VERSION 5.7 ;
  NOWIREEXTENSIONATPIN ON ;
  DIVIDERCHAR "/" ;
  BUSBITCHARS "[]" ;
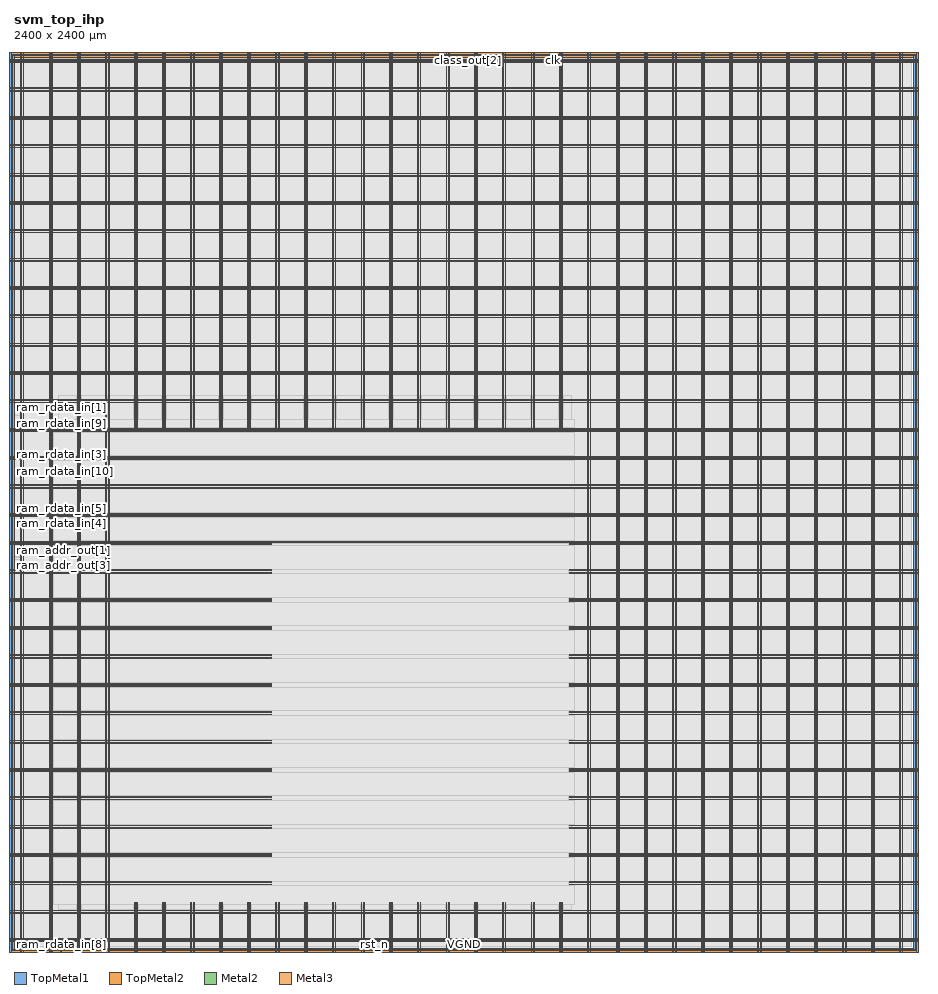
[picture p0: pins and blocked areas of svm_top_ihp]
MACRO svm_top_ihp
  CLASS BLOCK ;
  FOREIGN svm_top_ihp ;
  ORIGIN 0.000 0.000 ;
  SIZE 2400.000 BY 2400.000 ;
  PIN VGND
    DIRECTION INOUT ;
    USE GROUND ;
    PORT
      LAYER TopMetal1 ;
        RECT -10.740 -1.380 -5.740 2397.900 ;
    END
    PORT
      LAYER TopMetal1 ;
        RECT 2405.740 -1.380 2410.740 2397.900 ;
    END
    PORT
      LAYER TopMetal2 ;
        RECT -10.740 -1.380 2410.740 3.620 ;
    END
    PORT
      LAYER TopMetal2 ;
        RECT -10.740 2392.900 2410.740 2397.900 ;
    END
    PORT
      LAYER TopMetal1 ;
        RECT 24.460 -1.380 26.660 2397.900 ;
    END
    PORT
      LAYER TopMetal1 ;
        RECT 100.060 -1.380 102.260 2397.900 ;
    END
    PORT
      LAYER TopMetal1 ;
        RECT 175.660 -1.380 177.860 2397.900 ;
    END
    PORT
      LAYER TopMetal1 ;
        RECT 251.260 -1.380 253.460 2397.900 ;
    END
    PORT
      LAYER TopMetal1 ;
        RECT 326.860 -1.380 329.060 131.600 ;
    END
    PORT
      LAYER TopMetal1 ;
        RECT 326.860 1387.620 329.060 2397.900 ;
    END
    PORT
      LAYER TopMetal1 ;
        RECT 402.460 -1.380 404.660 131.600 ;
    END
    PORT
      LAYER TopMetal1 ;
        RECT 402.460 1387.620 404.660 2397.900 ;
    END
    PORT
      LAYER TopMetal1 ;
        RECT 478.060 -1.380 480.260 131.600 ;
    END
    PORT
      LAYER TopMetal1 ;
        RECT 478.060 1387.620 480.260 2397.900 ;
    END
    PORT
      LAYER TopMetal1 ;
        RECT 553.660 -1.380 555.860 131.600 ;
    END
    PORT
      LAYER TopMetal1 ;
        RECT 553.660 1387.620 555.860 2397.900 ;
    END
    PORT
      LAYER TopMetal1 ;
        RECT 629.260 -1.380 631.460 131.600 ;
    END
    PORT
      LAYER TopMetal1 ;
        RECT 629.260 1387.620 631.460 2397.900 ;
    END
    PORT
      LAYER TopMetal1 ;
        RECT 704.860 -1.380 707.060 131.600 ;
    END
    PORT
      LAYER TopMetal1 ;
        RECT 704.860 1387.620 707.060 2397.900 ;
    END
    PORT
      LAYER TopMetal1 ;
        RECT 780.460 -1.380 782.660 131.600 ;
    END
    PORT
      LAYER TopMetal1 ;
        RECT 780.460 1387.620 782.660 2397.900 ;
    END
    PORT
      LAYER TopMetal1 ;
        RECT 856.060 -1.380 858.260 131.600 ;
    END
    PORT
      LAYER TopMetal1 ;
        RECT 856.060 1387.620 858.260 2397.900 ;
    END
    PORT
      LAYER TopMetal1 ;
        RECT 931.660 -1.380 933.860 131.600 ;
    END
    PORT
      LAYER TopMetal1 ;
        RECT 931.660 1387.620 933.860 2397.900 ;
    END
    PORT
      LAYER TopMetal1 ;
        RECT 1007.260 -1.380 1009.460 131.600 ;
    END
    PORT
      LAYER TopMetal1 ;
        RECT 1007.260 1387.620 1009.460 2397.900 ;
    END
    PORT
      LAYER TopMetal1 ;
        RECT 1082.860 -1.380 1085.060 131.600 ;
    END
    PORT
      LAYER TopMetal1 ;
        RECT 1082.860 1387.620 1085.060 2397.900 ;
    END
    PORT
      LAYER TopMetal1 ;
        RECT 1158.460 -1.380 1160.660 131.600 ;
    END
    PORT
      LAYER TopMetal1 ;
        RECT 1158.460 1387.620 1160.660 2397.900 ;
    END
    PORT
      LAYER TopMetal1 ;
        RECT 1234.060 -1.380 1236.260 131.600 ;
    END
    PORT
      LAYER TopMetal1 ;
        RECT 1234.060 1387.620 1236.260 2397.900 ;
    END
    PORT
      LAYER TopMetal1 ;
        RECT 1309.660 -1.380 1311.860 131.600 ;
    END
    PORT
      LAYER TopMetal1 ;
        RECT 1309.660 1387.620 1311.860 2397.900 ;
    END
    PORT
      LAYER TopMetal1 ;
        RECT 1385.260 -1.380 1387.460 131.600 ;
    END
    PORT
      LAYER TopMetal1 ;
        RECT 1385.260 1387.620 1387.460 2397.900 ;
    END
    PORT
      LAYER TopMetal1 ;
        RECT 1460.860 -1.380 1463.060 131.600 ;
    END
    PORT
      LAYER TopMetal1 ;
        RECT 1460.860 1387.620 1463.060 2397.900 ;
    END
    PORT
      LAYER TopMetal1 ;
        RECT 1536.460 -1.380 1538.660 2397.900 ;
    END
    PORT
      LAYER TopMetal1 ;
        RECT 1612.060 -1.380 1614.260 2397.900 ;
    END
    PORT
      LAYER TopMetal1 ;
        RECT 1687.660 -1.380 1689.860 2397.900 ;
    END
    PORT
      LAYER TopMetal1 ;
        RECT 1763.260 -1.380 1765.460 2397.900 ;
    END
    PORT
      LAYER TopMetal1 ;
        RECT 1838.860 -1.380 1841.060 2397.900 ;
    END
    PORT
      LAYER TopMetal1 ;
        RECT 1914.460 -1.380 1916.660 2397.900 ;
    END
    PORT
      LAYER TopMetal1 ;
        RECT 1990.060 -1.380 1992.260 2397.900 ;
    END
    PORT
      LAYER TopMetal1 ;
        RECT 2065.660 -1.380 2067.860 2397.900 ;
    END
    PORT
      LAYER TopMetal1 ;
        RECT 2141.260 -1.380 2143.460 2397.900 ;
    END
    PORT
      LAYER TopMetal1 ;
        RECT 2216.860 -1.380 2219.060 2397.900 ;
    END
    PORT
      LAYER TopMetal1 ;
        RECT 2292.460 -1.380 2294.660 2397.900 ;
    END
    PORT
      LAYER TopMetal1 ;
        RECT 2368.060 -1.380 2370.260 2397.900 ;
    END
    PORT
      LAYER TopMetal2 ;
        RECT -10.740 33.820 2410.740 36.020 ;
    END
    PORT
      LAYER TopMetal2 ;
        RECT -10.740 109.420 2410.740 111.620 ;
    END
    PORT
      LAYER TopMetal2 ;
        RECT -10.740 185.020 685.880 187.220 ;
    END
    PORT
      LAYER TopMetal2 ;
        RECT -10.740 260.620 685.880 262.820 ;
    END
    PORT
      LAYER TopMetal2 ;
        RECT -10.740 336.220 685.880 338.420 ;
    END
    PORT
      LAYER TopMetal2 ;
        RECT -10.740 411.820 685.880 414.020 ;
    END
    PORT
      LAYER TopMetal2 ;
        RECT -10.740 487.420 685.880 489.620 ;
    END
    PORT
      LAYER TopMetal2 ;
        RECT -10.740 563.020 685.880 565.220 ;
    END
    PORT
      LAYER TopMetal2 ;
        RECT -10.740 638.620 685.880 640.820 ;
    END
    PORT
      LAYER TopMetal2 ;
        RECT -10.740 714.220 685.880 716.420 ;
    END
    PORT
      LAYER TopMetal2 ;
        RECT -10.740 789.820 685.880 792.020 ;
    END
    PORT
      LAYER TopMetal2 ;
        RECT -10.740 865.420 685.880 867.620 ;
    END
    PORT
      LAYER TopMetal2 ;
        RECT -10.740 941.020 685.880 943.220 ;
    END
    PORT
      LAYER TopMetal2 ;
        RECT -10.740 1016.620 685.880 1018.820 ;
    END
    PORT
      LAYER TopMetal2 ;
        RECT -10.740 1092.220 2410.740 1094.420 ;
    END
    PORT
      LAYER TopMetal2 ;
        RECT -10.740 1167.820 2410.740 1170.020 ;
    END
    PORT
      LAYER TopMetal2 ;
        RECT -10.740 1243.420 2410.740 1245.620 ;
    END
    PORT
      LAYER TopMetal2 ;
        RECT -10.740 1319.020 2410.740 1321.220 ;
    END
    PORT
      LAYER TopMetal2 ;
        RECT -10.740 1394.620 2410.740 1396.820 ;
    END
    PORT
      LAYER TopMetal2 ;
        RECT -10.740 1470.220 2410.740 1472.420 ;
    END
    PORT
      LAYER TopMetal2 ;
        RECT -10.740 1545.820 2410.740 1548.020 ;
    END
    PORT
      LAYER TopMetal2 ;
        RECT -10.740 1621.420 2410.740 1623.620 ;
    END
    PORT
      LAYER TopMetal2 ;
        RECT -10.740 1697.020 2410.740 1699.220 ;
    END
    PORT
      LAYER TopMetal2 ;
        RECT -10.740 1772.620 2410.740 1774.820 ;
    END
    PORT
      LAYER TopMetal2 ;
        RECT -10.740 1848.220 2410.740 1850.420 ;
    END
    PORT
      LAYER TopMetal2 ;
        RECT -10.740 1923.820 2410.740 1926.020 ;
    END
    PORT
      LAYER TopMetal2 ;
        RECT -10.740 1999.420 2410.740 2001.620 ;
    END
    PORT
      LAYER TopMetal2 ;
        RECT -10.740 2075.020 2410.740 2077.220 ;
    END
    PORT
      LAYER TopMetal2 ;
        RECT -10.740 2150.620 2410.740 2152.820 ;
    END
    PORT
      LAYER TopMetal2 ;
        RECT -10.740 2226.220 2410.740 2228.420 ;
    END
    PORT
      LAYER TopMetal2 ;
        RECT -10.740 2301.820 2410.740 2304.020 ;
    END
    PORT
      LAYER TopMetal2 ;
        RECT -10.740 2377.420 2410.740 2379.620 ;
    END
    PORT
      LAYER TopMetal2 ;
        RECT 1480.200 185.020 2410.740 187.220 ;
    END
    PORT
      LAYER TopMetal2 ;
        RECT 1480.200 260.620 2410.740 262.820 ;
    END
    PORT
      LAYER TopMetal2 ;
        RECT 1480.200 336.220 2410.740 338.420 ;
    END
    PORT
      LAYER TopMetal2 ;
        RECT 1480.200 411.820 2410.740 414.020 ;
    END
    PORT
      LAYER TopMetal2 ;
        RECT 1480.200 487.420 2410.740 489.620 ;
    END
    PORT
      LAYER TopMetal2 ;
        RECT 1480.200 563.020 2410.740 565.220 ;
    END
    PORT
      LAYER TopMetal2 ;
        RECT 1480.200 638.620 2410.740 640.820 ;
    END
    PORT
      LAYER TopMetal2 ;
        RECT 1480.200 714.220 2410.740 716.420 ;
    END
    PORT
      LAYER TopMetal2 ;
        RECT 1480.200 789.820 2410.740 792.020 ;
    END
    PORT
      LAYER TopMetal2 ;
        RECT 1480.200 865.420 2410.740 867.620 ;
    END
    PORT
      LAYER TopMetal2 ;
        RECT 1480.200 941.020 2410.740 943.220 ;
    END
    PORT
      LAYER TopMetal2 ;
        RECT 1480.200 1016.620 2410.740 1018.820 ;
    END
  END VGND
  PIN VPWR
    DIRECTION INOUT ;
    USE POWER ;
    PORT
      LAYER TopMetal1 ;
        RECT -3.740 5.620 1.260 2390.900 ;
    END
    PORT
      LAYER TopMetal1 ;
        RECT 2398.740 5.620 2403.740 2390.900 ;
    END
    PORT
      LAYER TopMetal2 ;
        RECT -3.740 5.620 2403.740 10.620 ;
    END
    PORT
      LAYER TopMetal2 ;
        RECT -3.740 2385.900 2403.740 2390.900 ;
    END
    PORT
      LAYER TopMetal1 ;
        RECT 18.260 -1.380 20.460 2397.900 ;
    END
    PORT
      LAYER TopMetal1 ;
        RECT 93.860 -1.380 96.060 2397.900 ;
    END
    PORT
      LAYER TopMetal1 ;
        RECT 169.460 -1.380 171.660 2397.900 ;
    END
    PORT
      LAYER TopMetal1 ;
        RECT 245.060 -1.380 247.260 2397.900 ;
    END
    PORT
      LAYER TopMetal1 ;
        RECT 320.660 -1.380 322.860 131.600 ;
    END
    PORT
      LAYER TopMetal1 ;
        RECT 320.660 1387.620 322.860 2397.900 ;
    END
    PORT
      LAYER TopMetal1 ;
        RECT 396.260 -1.380 398.460 131.600 ;
    END
    PORT
      LAYER TopMetal1 ;
        RECT 396.260 1387.620 398.460 2397.900 ;
    END
    PORT
      LAYER TopMetal1 ;
        RECT 471.860 -1.380 474.060 131.600 ;
    END
    PORT
      LAYER TopMetal1 ;
        RECT 471.860 1387.620 474.060 2397.900 ;
    END
    PORT
      LAYER TopMetal1 ;
        RECT 547.460 -1.380 549.660 131.600 ;
    END
    PORT
      LAYER TopMetal1 ;
        RECT 547.460 1387.620 549.660 2397.900 ;
    END
    PORT
      LAYER TopMetal1 ;
        RECT 623.060 -1.380 625.260 131.600 ;
    END
    PORT
      LAYER TopMetal1 ;
        RECT 623.060 1387.620 625.260 2397.900 ;
    END
    PORT
      LAYER TopMetal1 ;
        RECT 698.660 -1.380 700.860 131.600 ;
    END
    PORT
      LAYER TopMetal1 ;
        RECT 698.660 1387.620 700.860 2397.900 ;
    END
    PORT
      LAYER TopMetal1 ;
        RECT 774.260 -1.380 776.460 131.600 ;
    END
    PORT
      LAYER TopMetal1 ;
        RECT 774.260 1387.620 776.460 2397.900 ;
    END
    PORT
      LAYER TopMetal1 ;
        RECT 849.860 -1.380 852.060 131.600 ;
    END
    PORT
      LAYER TopMetal1 ;
        RECT 849.860 1387.620 852.060 2397.900 ;
    END
    PORT
      LAYER TopMetal1 ;
        RECT 925.460 -1.380 927.660 131.600 ;
    END
    PORT
      LAYER TopMetal1 ;
        RECT 925.460 1387.620 927.660 2397.900 ;
    END
    PORT
      LAYER TopMetal1 ;
        RECT 1001.060 -1.380 1003.260 131.600 ;
    END
    PORT
      LAYER TopMetal1 ;
        RECT 1001.060 1387.620 1003.260 2397.900 ;
    END
    PORT
      LAYER TopMetal1 ;
        RECT 1076.660 -1.380 1078.860 131.600 ;
    END
    PORT
      LAYER TopMetal1 ;
        RECT 1076.660 1387.620 1078.860 2397.900 ;
    END
    PORT
      LAYER TopMetal1 ;
        RECT 1152.260 -1.380 1154.460 131.600 ;
    END
    PORT
      LAYER TopMetal1 ;
        RECT 1152.260 1387.620 1154.460 2397.900 ;
    END
    PORT
      LAYER TopMetal1 ;
        RECT 1227.860 -1.380 1230.060 131.600 ;
    END
    PORT
      LAYER TopMetal1 ;
        RECT 1227.860 1387.620 1230.060 2397.900 ;
    END
    PORT
      LAYER TopMetal1 ;
        RECT 1303.460 -1.380 1305.660 131.600 ;
    END
    PORT
      LAYER TopMetal1 ;
        RECT 1303.460 1387.620 1305.660 2397.900 ;
    END
    PORT
      LAYER TopMetal1 ;
        RECT 1379.060 -1.380 1381.260 131.600 ;
    END
    PORT
      LAYER TopMetal1 ;
        RECT 1379.060 1387.620 1381.260 2397.900 ;
    END
    PORT
      LAYER TopMetal1 ;
        RECT 1454.660 -1.380 1456.860 131.600 ;
    END
    PORT
      LAYER TopMetal1 ;
        RECT 1454.660 1387.620 1456.860 2397.900 ;
    END
    PORT
      LAYER TopMetal1 ;
        RECT 1530.260 -1.380 1532.460 2397.900 ;
    END
    PORT
      LAYER TopMetal1 ;
        RECT 1605.860 -1.380 1608.060 2397.900 ;
    END
    PORT
      LAYER TopMetal1 ;
        RECT 1681.460 -1.380 1683.660 2397.900 ;
    END
    PORT
      LAYER TopMetal1 ;
        RECT 1757.060 -1.380 1759.260 2397.900 ;
    END
    PORT
      LAYER TopMetal1 ;
        RECT 1832.660 -1.380 1834.860 2397.900 ;
    END
    PORT
      LAYER TopMetal1 ;
        RECT 1908.260 -1.380 1910.460 2397.900 ;
    END
    PORT
      LAYER TopMetal1 ;
        RECT 1983.860 -1.380 1986.060 2397.900 ;
    END
    PORT
      LAYER TopMetal1 ;
        RECT 2059.460 -1.380 2061.660 2397.900 ;
    END
    PORT
      LAYER TopMetal1 ;
        RECT 2135.060 -1.380 2137.260 2397.900 ;
    END
    PORT
      LAYER TopMetal1 ;
        RECT 2210.660 -1.380 2212.860 2397.900 ;
    END
    PORT
      LAYER TopMetal1 ;
        RECT 2286.260 -1.380 2288.460 2397.900 ;
    END
    PORT
      LAYER TopMetal1 ;
        RECT 2361.860 -1.380 2364.060 2397.900 ;
    END
    PORT
      LAYER TopMetal2 ;
        RECT -10.740 27.620 2410.740 29.820 ;
    END
    PORT
      LAYER TopMetal2 ;
        RECT -10.740 103.220 2410.740 105.420 ;
    END
    PORT
      LAYER TopMetal2 ;
        RECT -10.740 178.820 685.880 181.020 ;
    END
    PORT
      LAYER TopMetal2 ;
        RECT -10.740 254.420 685.880 256.620 ;
    END
    PORT
      LAYER TopMetal2 ;
        RECT -10.740 330.020 685.880 332.220 ;
    END
    PORT
      LAYER TopMetal2 ;
        RECT -10.740 405.620 685.880 407.820 ;
    END
    PORT
      LAYER TopMetal2 ;
        RECT -10.740 481.220 685.880 483.420 ;
    END
    PORT
      LAYER TopMetal2 ;
        RECT -10.740 556.820 685.880 559.020 ;
    END
    PORT
      LAYER TopMetal2 ;
        RECT -10.740 632.420 685.880 634.620 ;
    END
    PORT
      LAYER TopMetal2 ;
        RECT -10.740 708.020 685.880 710.220 ;
    END
    PORT
      LAYER TopMetal2 ;
        RECT -10.740 783.620 685.880 785.820 ;
    END
    PORT
      LAYER TopMetal2 ;
        RECT -10.740 859.220 685.880 861.420 ;
    END
    PORT
      LAYER TopMetal2 ;
        RECT -10.740 934.820 685.880 937.020 ;
    END
    PORT
      LAYER TopMetal2 ;
        RECT -10.740 1010.420 685.880 1012.620 ;
    END
    PORT
      LAYER TopMetal2 ;
        RECT -10.740 1086.020 685.880 1088.220 ;
    END
    PORT
      LAYER TopMetal2 ;
        RECT -10.740 1161.620 2410.740 1163.820 ;
    END
    PORT
      LAYER TopMetal2 ;
        RECT -10.740 1237.220 2410.740 1239.420 ;
    END
    PORT
      LAYER TopMetal2 ;
        RECT -10.740 1312.820 2410.740 1315.020 ;
    END
    PORT
      LAYER TopMetal2 ;
        RECT -10.740 1388.420 2410.740 1390.620 ;
    END
    PORT
      LAYER TopMetal2 ;
        RECT -10.740 1464.020 2410.740 1466.220 ;
    END
    PORT
      LAYER TopMetal2 ;
        RECT -10.740 1539.620 2410.740 1541.820 ;
    END
    PORT
      LAYER TopMetal2 ;
        RECT -10.740 1615.220 2410.740 1617.420 ;
    END
    PORT
      LAYER TopMetal2 ;
        RECT -10.740 1690.820 2410.740 1693.020 ;
    END
    PORT
      LAYER TopMetal2 ;
        RECT -10.740 1766.420 2410.740 1768.620 ;
    END
    PORT
      LAYER TopMetal2 ;
        RECT -10.740 1842.020 2410.740 1844.220 ;
    END
    PORT
      LAYER TopMetal2 ;
        RECT -10.740 1917.620 2410.740 1919.820 ;
    END
    PORT
      LAYER TopMetal2 ;
        RECT -10.740 1993.220 2410.740 1995.420 ;
    END
    PORT
      LAYER TopMetal2 ;
        RECT -10.740 2068.820 2410.740 2071.020 ;
    END
    PORT
      LAYER TopMetal2 ;
        RECT -10.740 2144.420 2410.740 2146.620 ;
    END
    PORT
      LAYER TopMetal2 ;
        RECT -10.740 2220.020 2410.740 2222.220 ;
    END
    PORT
      LAYER TopMetal2 ;
        RECT -10.740 2295.620 2410.740 2297.820 ;
    END
    PORT
      LAYER TopMetal2 ;
        RECT -10.740 2371.220 2410.740 2373.420 ;
    END
    PORT
      LAYER TopMetal2 ;
        RECT 1480.200 178.820 2410.740 181.020 ;
    END
    PORT
      LAYER TopMetal2 ;
        RECT 1480.200 254.420 2410.740 256.620 ;
    END
    PORT
      LAYER TopMetal2 ;
        RECT 1480.200 330.020 2410.740 332.220 ;
    END
    PORT
      LAYER TopMetal2 ;
        RECT 1480.200 405.620 2410.740 407.820 ;
    END
    PORT
      LAYER TopMetal2 ;
        RECT 1480.200 481.220 2410.740 483.420 ;
    END
    PORT
      LAYER TopMetal2 ;
        RECT 1480.200 556.820 2410.740 559.020 ;
    END
    PORT
      LAYER TopMetal2 ;
        RECT 1480.200 632.420 2410.740 634.620 ;
    END
    PORT
      LAYER TopMetal2 ;
        RECT 1480.200 708.020 2410.740 710.220 ;
    END
    PORT
      LAYER TopMetal2 ;
        RECT 1480.200 783.620 2410.740 785.820 ;
    END
    PORT
      LAYER TopMetal2 ;
        RECT 1480.200 859.220 2410.740 861.420 ;
    END
    PORT
      LAYER TopMetal2 ;
        RECT 1480.200 934.820 2410.740 937.020 ;
    END
    PORT
      LAYER TopMetal2 ;
        RECT 1480.200 1010.420 2410.740 1012.620 ;
    END
    PORT
      LAYER TopMetal2 ;
        RECT 1480.200 1086.020 2410.740 1088.220 ;
    END
  END VPWR
  PIN class_out[0]
    DIRECTION OUTPUT ;
    USE SIGNAL ;
    ANTENNADIFFAREA 0.708600 ;
    PORT
      LAYER Metal2 ;
        RECT 1211.800 2399.600 1212.200 2400.000 ;
    END
  END class_out[0]
  PIN class_out[1]
    DIRECTION OUTPUT ;
    USE SIGNAL ;
    ANTENNADIFFAREA 0.708600 ;
    PORT
      LAYER Metal2 ;
        RECT 1210.840 2399.600 1211.240 2400.000 ;
    END
  END class_out[1]
  PIN class_out[2]
    DIRECTION OUTPUT ;
    USE SIGNAL ;
    ANTENNADIFFAREA 0.708600 ;
    PORT
      LAYER Metal2 ;
        RECT 1209.880 2399.600 1210.280 2400.000 ;
    END
  END class_out[2]
  PIN clk
    DIRECTION INPUT ;
    USE SIGNAL ;
    ANTENNAGATEAREA 2.901600 ;
    PORT
      LAYER Metal2 ;
        RECT 1437.400 2399.600 1437.800 2400.000 ;
    END
  END clk
  PIN done
    DIRECTION OUTPUT ;
    USE SIGNAL ;
    ANTENNADIFFAREA 0.708600 ;
    PORT
      LAYER Metal2 ;
        RECT 1190.680 2399.600 1191.080 2400.000 ;
    END
  END done
  PIN error
    DIRECTION OUTPUT ;
    USE SIGNAL ;
    ANTENNADIFFAREA 0.708600 ;
    PORT
      LAYER Metal2 ;
        RECT 1221.400 2399.600 1221.800 2400.000 ;
    END
  END error
  PIN error_code[0]
    DIRECTION OUTPUT ;
    USE SIGNAL ;
    ANTENNADIFFAREA 0.708600 ;
    PORT
      LAYER Metal2 ;
        RECT 1242.520 2399.600 1242.920 2400.000 ;
    END
  END error_code[0]
  PIN error_code[1]
    DIRECTION OUTPUT ;
    USE SIGNAL ;
    ANTENNADIFFAREA 0.708600 ;
    PORT
      LAYER Metal2 ;
        RECT 1245.400 2399.600 1245.800 2400.000 ;
    END
  END error_code[1]
  PIN error_code[2]
    DIRECTION OUTPUT ;
    USE SIGNAL ;
    ANTENNADIFFAREA 0.708600 ;
    PORT
      LAYER Metal2 ;
        RECT 1244.440 2399.600 1244.840 2400.000 ;
    END
  END error_code[2]
  PIN error_code[3]
    DIRECTION OUTPUT ;
    USE SIGNAL ;
    ANTENNADIFFAREA 0.708600 ;
    PORT
      LAYER Metal2 ;
        RECT 1208.920 2399.600 1209.320 2400.000 ;
    END
  END error_code[3]
  PIN irq_done
    DIRECTION OUTPUT ;
    USE SIGNAL ;
    ANTENNADIFFAREA 0.708600 ;
    PORT
      LAYER Metal2 ;
        RECT 1113.880 2399.600 1114.280 2400.000 ;
    END
  END irq_done
  PIN irq_sample_rdy
    DIRECTION OUTPUT ;
    USE SIGNAL ;
    ANTENNADIFFAREA 0.708600 ;
    PORT
      LAYER Metal2 ;
        RECT 1153.240 2399.600 1153.640 2400.000 ;
    END
  END irq_sample_rdy
  PIN ram_addr_out[0]
    DIRECTION OUTPUT ;
    USE SIGNAL ;
    ANTENNADIFFAREA 0.708600 ;
    PORT
      LAYER Metal3 ;
        RECT 0.000 1072.060 0.400 1072.460 ;
    END
  END ram_addr_out[0]
  PIN ram_addr_out[10]
    DIRECTION OUTPUT ;
    USE SIGNAL ;
    ANTENNADIFFAREA 0.708600 ;
    PORT
      LAYER Metal2 ;
        RECT 1071.640 2399.600 1072.040 2400.000 ;
    END
  END ram_addr_out[10]
  PIN ram_addr_out[11]
    DIRECTION OUTPUT ;
    USE SIGNAL ;
    ANTENNADIFFAREA 0.708600 ;
    PORT
      LAYER Metal2 ;
        RECT 1073.560 2399.600 1073.960 2400.000 ;
    END
  END ram_addr_out[11]
  PIN ram_addr_out[12]
    DIRECTION OUTPUT ;
    USE SIGNAL ;
    ANTENNADIFFAREA 0.708600 ;
    PORT
      LAYER Metal2 ;
        RECT 1075.480 2399.600 1075.880 2400.000 ;
    END
  END ram_addr_out[12]
  PIN ram_addr_out[13]
    DIRECTION OUTPUT ;
    USE SIGNAL ;
    ANTENNADIFFAREA 0.708600 ;
    PORT
      LAYER Metal2 ;
        RECT 1074.520 2399.600 1074.920 2400.000 ;
    END
  END ram_addr_out[13]
  PIN ram_addr_out[14]
    DIRECTION OUTPUT ;
    USE SIGNAL ;
    ANTENNADIFFAREA 0.708600 ;
    PORT
      LAYER Metal2 ;
        RECT 1072.600 2399.600 1073.000 2400.000 ;
    END
  END ram_addr_out[14]
  PIN ram_addr_out[15]
    DIRECTION OUTPUT ;
    USE SIGNAL ;
    ANTENNADIFFAREA 0.708600 ;
    PORT
      LAYER Metal2 ;
        RECT 1067.800 2399.600 1068.200 2400.000 ;
    END
  END ram_addr_out[15]
  PIN ram_addr_out[16]
    DIRECTION OUTPUT ;
    USE SIGNAL ;
    ANTENNADIFFAREA 0.708600 ;
    PORT
      LAYER Metal2 ;
        RECT 1041.880 2399.600 1042.280 2400.000 ;
    END
  END ram_addr_out[16]
  PIN ram_addr_out[17]
    DIRECTION OUTPUT ;
    USE SIGNAL ;
    ANTENNADIFFAREA 0.708600 ;
    PORT
      LAYER Metal2 ;
        RECT 1049.560 2399.600 1049.960 2400.000 ;
    END
  END ram_addr_out[17]
  PIN ram_addr_out[18]
    DIRECTION OUTPUT ;
    USE SIGNAL ;
    ANTENNADIFFAREA 0.708600 ;
    PORT
      LAYER Metal2 ;
        RECT 1048.600 2399.600 1049.000 2400.000 ;
    END
  END ram_addr_out[18]
  PIN ram_addr_out[1]
    DIRECTION OUTPUT ;
    USE SIGNAL ;
    ANTENNADIFFAREA 0.708600 ;
    PORT
      LAYER Metal3 ;
        RECT 0.000 1070.380 0.400 1070.780 ;
    END
  END ram_addr_out[1]
  PIN ram_addr_out[2]
    DIRECTION OUTPUT ;
    USE SIGNAL ;
    ANTENNADIFFAREA 0.708600 ;
    PORT
      LAYER Metal3 ;
        RECT 0.000 1058.620 0.400 1059.020 ;
    END
  END ram_addr_out[2]
  PIN ram_addr_out[3]
    DIRECTION OUTPUT ;
    USE SIGNAL ;
    ANTENNADIFFAREA 0.708600 ;
    PORT
      LAYER Metal3 ;
        RECT 0.000 1051.900 0.400 1052.300 ;
    END
  END ram_addr_out[3]
  PIN ram_addr_out[4]
    DIRECTION OUTPUT ;
    USE SIGNAL ;
    ANTENNADIFFAREA 0.708600 ;
    PORT
      LAYER Metal3 ;
        RECT 0.000 1038.460 0.400 1038.860 ;
    END
  END ram_addr_out[4]
  PIN ram_addr_out[5]
    DIRECTION OUTPUT ;
    USE SIGNAL ;
    ANTENNADIFFAREA 0.708600 ;
    PORT
      LAYER Metal3 ;
        RECT 0.000 1052.740 0.400 1053.140 ;
    END
  END ram_addr_out[5]
  PIN ram_addr_out[6]
    DIRECTION OUTPUT ;
    USE SIGNAL ;
    ANTENNADIFFAREA 0.708600 ;
    PORT
      LAYER Metal3 ;
        RECT 0.000 1046.860 0.400 1047.260 ;
    END
  END ram_addr_out[6]
  PIN ram_addr_out[7]
    DIRECTION OUTPUT ;
    USE SIGNAL ;
    ANTENNADIFFAREA 0.708600 ;
    PORT
      LAYER Metal3 ;
        RECT 0.000 1071.220 0.400 1071.620 ;
    END
  END ram_addr_out[7]
  PIN ram_addr_out[8]
    DIRECTION OUTPUT ;
    USE SIGNAL ;
    ANTENNADIFFAREA 0.708600 ;
    PORT
      LAYER Metal2 ;
        RECT 1066.840 2399.600 1067.240 2400.000 ;
    END
  END ram_addr_out[8]
  PIN ram_addr_out[9]
    DIRECTION OUTPUT ;
    USE SIGNAL ;
    ANTENNADIFFAREA 0.708600 ;
    PORT
      LAYER Metal2 ;
        RECT 1064.920 2399.600 1065.320 2400.000 ;
    END
  END ram_addr_out[9]
  PIN ram_rdata_in[0]
    DIRECTION INPUT ;
    USE SIGNAL ;
    ANTENNAGATEAREA 0.109200 ;
    PORT
      LAYER Metal3 ;
        RECT 0.000 1464.340 0.400 1464.740 ;
    END
  END ram_rdata_in[0]
  PIN ram_rdata_in[10]
    DIRECTION INPUT ;
    USE SIGNAL ;
    ANTENNAGATEAREA 0.109200 ;
    PORT
      LAYER Metal3 ;
        RECT 0.000 1281.220 0.400 1281.620 ;
    END
  END ram_rdata_in[10]
  PIN ram_rdata_in[11]
    DIRECTION INPUT ;
    USE SIGNAL ;
    ANTENNAGATEAREA 0.109200 ;
    PORT
      LAYER Metal3 ;
        RECT 0.000 1451.740 0.400 1452.140 ;
    END
  END ram_rdata_in[11]
  PIN ram_rdata_in[12]
    DIRECTION INPUT ;
    USE SIGNAL ;
    ANTENNAGATEAREA 0.109200 ;
    PORT
      LAYER Metal3 ;
        RECT 0.000 1329.100 0.400 1329.500 ;
    END
  END ram_rdata_in[12]
  PIN ram_rdata_in[13]
    DIRECTION INPUT ;
    USE SIGNAL ;
    ANTENNAGATEAREA 0.109200 ;
    PORT
      LAYER Metal3 ;
        RECT 0.000 1328.260 0.400 1328.660 ;
    END
  END ram_rdata_in[13]
  PIN ram_rdata_in[14]
    DIRECTION INPUT ;
    USE SIGNAL ;
    ANTENNAGATEAREA 0.109200 ;
    PORT
      LAYER Metal3 ;
        RECT 0.000 1291.300 0.400 1291.700 ;
    END
  END ram_rdata_in[14]
  PIN ram_rdata_in[15]
    DIRECTION INPUT ;
    USE SIGNAL ;
    ANTENNAGATEAREA 0.109200 ;
    PORT
      LAYER Metal3 ;
        RECT 0.000 1461.820 0.400 1462.220 ;
    END
  END ram_rdata_in[15]
  PIN ram_rdata_in[1]
    DIRECTION INPUT ;
    USE SIGNAL ;
    ANTENNAGATEAREA 0.109200 ;
    PORT
      LAYER Metal3 ;
        RECT 0.000 1450.900 0.400 1451.300 ;
    END
  END ram_rdata_in[1]
  PIN ram_rdata_in[2]
    DIRECTION INPUT ;
    USE SIGNAL ;
    ANTENNAGATEAREA 0.109200 ;
    PORT
      LAYER Metal3 ;
        RECT 0.000 1463.500 0.400 1463.900 ;
    END
  END ram_rdata_in[2]
  PIN ram_rdata_in[3]
    DIRECTION INPUT ;
    USE SIGNAL ;
    ANTENNAGATEAREA 0.109200 ;
    PORT
      LAYER Metal3 ;
        RECT 0.000 1327.420 0.400 1327.820 ;
    END
  END ram_rdata_in[3]
  PIN ram_rdata_in[4]
    DIRECTION INPUT ;
    USE SIGNAL ;
    ANTENNAGATEAREA 0.109200 ;
    PORT
      LAYER Metal3 ;
        RECT 0.000 1142.620 0.400 1143.020 ;
    END
  END ram_rdata_in[4]
  PIN ram_rdata_in[5]
    DIRECTION INPUT ;
    USE SIGNAL ;
    ANTENNAGATEAREA 0.109200 ;
    PORT
      LAYER Metal3 ;
        RECT 0.000 1161.100 0.400 1161.500 ;
    END
  END ram_rdata_in[5]
  PIN ram_rdata_in[6]
    DIRECTION INPUT ;
    USE SIGNAL ;
    ANTENNAGATEAREA 0.109200 ;
    PORT
      LAYER Metal3 ;
        RECT 0.000 1459.300 0.400 1459.700 ;
    END
  END ram_rdata_in[6]
  PIN ram_rdata_in[7]
    DIRECTION INPUT ;
    USE SIGNAL ;
    ANTENNAGATEAREA 0.109200 ;
    PORT
      LAYER Metal3 ;
        RECT 0.000 1270.300 0.400 1270.700 ;
    END
  END ram_rdata_in[7]
  PIN ram_rdata_in[8]
    DIRECTION INPUT ;
    USE SIGNAL ;
    ANTENNAGATEAREA 0.109200 ;
    PORT
      LAYER Metal2 ;
        RECT 125.080 0.000 125.480 0.400 ;
    END
  END ram_rdata_in[8]
  PIN ram_rdata_in[9]
    DIRECTION INPUT ;
    USE SIGNAL ;
    ANTENNAGATEAREA 0.109200 ;
    PORT
      LAYER Metal3 ;
        RECT 0.000 1429.900 0.400 1430.300 ;
    END
  END ram_rdata_in[9]
  PIN ram_ren_out
    DIRECTION OUTPUT ;
    USE SIGNAL ;
    ANTENNADIFFAREA 0.708600 ;
    PORT
      LAYER Metal3 ;
        RECT 0.000 1077.100 0.400 1077.500 ;
    END
  END ram_ren_out
  PIN rst_n
    DIRECTION INPUT ;
    USE SIGNAL ;
    ANTENNAGATEAREA 0.109200 ;
    PORT
      LAYER Metal2 ;
        RECT 962.200 0.000 962.600 0.400 ;
    END
  END rst_n
  PIN sample_rdy
    DIRECTION OUTPUT ;
    USE SIGNAL ;
    ANTENNADIFFAREA 0.708600 ;
    PORT
      LAYER Metal2 ;
        RECT 1099.480 2399.600 1099.880 2400.000 ;
    END
  END sample_rdy
  PIN spi_csn
    DIRECTION INPUT ;
    USE SIGNAL ;
    ANTENNAGATEAREA 0.180700 ;
    PORT
      LAYER Metal2 ;
        RECT 1301.080 2399.600 1301.480 2400.000 ;
    END
  END spi_csn
  PIN spi_miso
    DIRECTION OUTPUT ;
    USE SIGNAL ;
    ANTENNADIFFAREA 0.708600 ;
    PORT
      LAYER Metal2 ;
        RECT 1119.640 2399.600 1120.040 2400.000 ;
    END
  END spi_miso
  PIN spi_mosi
    DIRECTION INPUT ;
    USE SIGNAL ;
    ANTENNAGATEAREA 0.180700 ;
    PORT
      LAYER Metal2 ;
        RECT 1262.680 2399.600 1263.080 2400.000 ;
    END
  END spi_mosi
  PIN spi_sclk
    DIRECTION INPUT ;
    USE SIGNAL ;
    ANTENNAGATEAREA 0.180700 ;
    PORT
      LAYER Metal2 ;
        RECT 1226.200 2399.600 1226.600 2400.000 ;
    END
  END spi_sclk
  OBS
      LAYER GatPoly ;
        RECT 5.760 14.970 2394.240 2381.550 ;
      LAYER Metal1 ;
        RECT 5.760 14.900 2394.240 2381.620 ;
      LAYER Metal2 ;
        RECT 6.135 2399.390 1041.670 2399.980 ;
        RECT 1042.490 2399.390 1048.390 2399.980 ;
        RECT 1049.210 2399.390 1049.350 2399.980 ;
        RECT 1050.170 2399.390 1064.710 2399.980 ;
        RECT 1065.530 2399.390 1066.630 2399.980 ;
        RECT 1067.450 2399.390 1067.590 2399.980 ;
        RECT 1068.410 2399.390 1071.430 2399.980 ;
        RECT 1072.250 2399.390 1072.390 2399.980 ;
        RECT 1073.210 2399.390 1073.350 2399.980 ;
        RECT 1074.170 2399.390 1074.310 2399.980 ;
        RECT 1075.130 2399.390 1075.270 2399.980 ;
        RECT 1076.090 2399.390 1099.270 2399.980 ;
        RECT 1100.090 2399.390 1113.670 2399.980 ;
        RECT 1114.490 2399.390 1119.430 2399.980 ;
        RECT 1120.250 2399.390 1153.030 2399.980 ;
        RECT 1153.850 2399.390 1190.470 2399.980 ;
        RECT 1191.290 2399.390 1208.710 2399.980 ;
        RECT 1209.530 2399.390 1209.670 2399.980 ;
        RECT 1210.490 2399.390 1210.630 2399.980 ;
        RECT 1211.450 2399.390 1211.590 2399.980 ;
        RECT 1212.410 2399.390 1221.190 2399.980 ;
        RECT 1222.010 2399.390 1225.990 2399.980 ;
        RECT 1226.810 2399.390 1242.310 2399.980 ;
        RECT 1243.130 2399.390 1244.230 2399.980 ;
        RECT 1245.050 2399.390 1245.190 2399.980 ;
        RECT 1246.010 2399.390 1262.470 2399.980 ;
        RECT 1263.290 2399.390 1300.870 2399.980 ;
        RECT 1301.690 2399.390 1437.190 2399.980 ;
        RECT 1438.010 2399.390 2370.080 2399.980 ;
        RECT 6.135 0.610 2370.080 2399.390 ;
        RECT 6.135 0.400 124.870 0.610 ;
        RECT 125.690 0.400 961.990 0.610 ;
        RECT 962.810 0.400 2370.080 0.610 ;
      LAYER Metal3 ;
        RECT 0.400 1464.950 2370.125 2384.440 ;
        RECT 0.610 1464.130 2370.125 1464.950 ;
        RECT 0.400 1464.110 2370.125 1464.130 ;
        RECT 0.610 1463.290 2370.125 1464.110 ;
        RECT 0.400 1462.430 2370.125 1463.290 ;
        RECT 0.610 1461.610 2370.125 1462.430 ;
        RECT 0.400 1459.910 2370.125 1461.610 ;
        RECT 0.610 1459.090 2370.125 1459.910 ;
        RECT 0.400 1452.350 2370.125 1459.090 ;
        RECT 0.610 1451.530 2370.125 1452.350 ;
        RECT 0.400 1451.510 2370.125 1451.530 ;
        RECT 0.610 1450.690 2370.125 1451.510 ;
        RECT 0.400 1430.510 2370.125 1450.690 ;
        RECT 0.610 1429.690 2370.125 1430.510 ;
        RECT 0.400 1329.710 2370.125 1429.690 ;
        RECT 0.610 1328.890 2370.125 1329.710 ;
        RECT 0.400 1328.870 2370.125 1328.890 ;
        RECT 0.610 1328.050 2370.125 1328.870 ;
        RECT 0.400 1328.030 2370.125 1328.050 ;
        RECT 0.610 1327.210 2370.125 1328.030 ;
        RECT 0.400 1291.910 2370.125 1327.210 ;
        RECT 0.610 1291.090 2370.125 1291.910 ;
        RECT 0.400 1281.830 2370.125 1291.090 ;
        RECT 0.610 1281.010 2370.125 1281.830 ;
        RECT 0.400 1270.910 2370.125 1281.010 ;
        RECT 0.610 1270.090 2370.125 1270.910 ;
        RECT 0.400 1161.710 2370.125 1270.090 ;
        RECT 0.610 1160.890 2370.125 1161.710 ;
        RECT 0.400 1143.230 2370.125 1160.890 ;
        RECT 0.610 1142.410 2370.125 1143.230 ;
        RECT 0.400 1077.710 2370.125 1142.410 ;
        RECT 0.610 1076.890 2370.125 1077.710 ;
        RECT 0.400 1072.670 2370.125 1076.890 ;
        RECT 0.610 1071.850 2370.125 1072.670 ;
        RECT 0.400 1071.830 2370.125 1071.850 ;
        RECT 0.610 1071.010 2370.125 1071.830 ;
        RECT 0.400 1070.990 2370.125 1071.010 ;
        RECT 0.610 1070.170 2370.125 1070.990 ;
        RECT 0.400 1059.230 2370.125 1070.170 ;
        RECT 0.610 1058.410 2370.125 1059.230 ;
        RECT 0.400 1053.350 2370.125 1058.410 ;
        RECT 0.610 1052.530 2370.125 1053.350 ;
        RECT 0.400 1052.510 2370.125 1052.530 ;
        RECT 0.610 1051.690 2370.125 1052.510 ;
        RECT 0.400 1047.470 2370.125 1051.690 ;
        RECT 0.610 1046.650 2370.125 1047.470 ;
        RECT 0.400 1039.070 2370.125 1046.650 ;
        RECT 0.610 1038.250 2370.125 1039.070 ;
        RECT 0.400 15.020 2370.125 1038.250 ;
      LAYER Metal4 ;
        RECT 18.440 14.975 2370.080 2381.545 ;
      LAYER Metal5 ;
        RECT 18.395 14.810 2370.125 2381.710 ;
      LAYER TopMetal1 ;
        RECT 118.260 114.490 167.820 1484.110 ;
        RECT 173.300 114.490 174.020 1484.110 ;
        RECT 179.500 114.490 243.420 1484.110 ;
        RECT 248.900 114.490 249.620 1484.110 ;
        RECT 255.100 1385.980 319.020 1484.110 ;
        RECT 324.500 1385.980 325.220 1484.110 ;
        RECT 330.700 1385.980 394.620 1484.110 ;
        RECT 400.100 1385.980 400.820 1484.110 ;
        RECT 406.300 1385.980 470.220 1484.110 ;
        RECT 475.700 1385.980 476.420 1484.110 ;
        RECT 481.900 1385.980 545.820 1484.110 ;
        RECT 551.300 1385.980 552.020 1484.110 ;
        RECT 557.500 1385.980 621.420 1484.110 ;
        RECT 626.900 1385.980 627.620 1484.110 ;
        RECT 633.100 1385.980 697.020 1484.110 ;
        RECT 702.500 1385.980 703.220 1484.110 ;
        RECT 708.700 1385.980 772.620 1484.110 ;
        RECT 778.100 1385.980 778.820 1484.110 ;
        RECT 784.300 1385.980 848.220 1484.110 ;
        RECT 853.700 1385.980 854.420 1484.110 ;
        RECT 859.900 1385.980 923.820 1484.110 ;
        RECT 929.300 1385.980 930.020 1484.110 ;
        RECT 935.500 1385.980 999.420 1484.110 ;
        RECT 1004.900 1385.980 1005.620 1484.110 ;
        RECT 1011.100 1385.980 1075.020 1484.110 ;
        RECT 1080.500 1385.980 1081.220 1484.110 ;
        RECT 1086.700 1385.980 1150.620 1484.110 ;
        RECT 1156.100 1385.980 1156.820 1484.110 ;
        RECT 1162.300 1385.980 1226.220 1484.110 ;
        RECT 1231.700 1385.980 1232.420 1484.110 ;
        RECT 1237.900 1385.980 1301.820 1484.110 ;
        RECT 1307.300 1385.980 1308.020 1484.110 ;
        RECT 1313.500 1385.980 1377.420 1484.110 ;
        RECT 1382.900 1385.980 1383.620 1484.110 ;
        RECT 1389.100 1385.980 1453.020 1484.110 ;
        RECT 1458.500 1385.980 1459.220 1484.110 ;
        RECT 1464.700 1385.980 1487.460 1484.110 ;
        RECT 255.100 133.240 1487.460 1385.980 ;
        RECT 255.100 114.490 319.020 133.240 ;
        RECT 324.500 114.490 325.220 133.240 ;
        RECT 330.700 114.490 394.620 133.240 ;
        RECT 400.100 114.490 400.820 133.240 ;
        RECT 406.300 114.490 470.220 133.240 ;
        RECT 475.700 114.490 476.420 133.240 ;
        RECT 481.900 114.490 545.820 133.240 ;
        RECT 551.300 114.490 552.020 133.240 ;
        RECT 557.500 114.490 621.420 133.240 ;
        RECT 626.900 114.490 627.620 133.240 ;
        RECT 633.100 114.490 697.020 133.240 ;
        RECT 702.500 114.490 703.220 133.240 ;
        RECT 708.700 114.490 772.620 133.240 ;
        RECT 778.100 114.490 778.820 133.240 ;
        RECT 784.300 114.490 848.220 133.240 ;
        RECT 853.700 114.490 854.420 133.240 ;
        RECT 859.900 114.490 923.820 133.240 ;
        RECT 929.300 114.490 930.020 133.240 ;
        RECT 935.500 114.490 999.420 133.240 ;
        RECT 1004.900 114.490 1005.620 133.240 ;
        RECT 1011.100 114.490 1075.020 133.240 ;
        RECT 1080.500 114.490 1081.220 133.240 ;
        RECT 1086.700 114.490 1150.620 133.240 ;
        RECT 1156.100 114.490 1156.820 133.240 ;
        RECT 1162.300 114.490 1226.220 133.240 ;
        RECT 1231.700 114.490 1232.420 133.240 ;
        RECT 1237.900 114.490 1301.820 133.240 ;
        RECT 1307.300 114.490 1308.020 133.240 ;
        RECT 1313.500 114.490 1377.420 133.240 ;
        RECT 1382.900 114.490 1383.620 133.240 ;
        RECT 1389.100 114.490 1453.020 133.240 ;
        RECT 1458.500 114.490 1459.220 133.240 ;
        RECT 1464.700 114.490 1487.460 133.240 ;
      LAYER TopMetal2 ;
        RECT 105.760 1398.820 1493.920 1421.220 ;
        RECT 105.760 1323.220 1493.920 1386.420 ;
        RECT 105.760 1247.620 1493.920 1310.820 ;
        RECT 105.760 1172.020 1493.920 1235.220 ;
        RECT 105.760 1096.420 1493.920 1159.620 ;
        RECT 687.880 1084.020 1478.200 1090.220 ;
        RECT 105.760 1020.820 1493.920 1084.020 ;
        RECT 687.880 1008.420 1478.200 1020.820 ;
        RECT 105.760 945.220 1493.920 1008.420 ;
        RECT 687.880 932.820 1478.200 945.220 ;
        RECT 105.760 869.620 1493.920 932.820 ;
        RECT 687.880 857.220 1478.200 869.620 ;
        RECT 105.760 794.020 1493.920 857.220 ;
        RECT 687.880 781.620 1478.200 794.020 ;
        RECT 105.760 718.420 1493.920 781.620 ;
        RECT 687.880 706.020 1478.200 718.420 ;
        RECT 105.760 642.820 1493.920 706.020 ;
        RECT 687.880 630.420 1478.200 642.820 ;
        RECT 105.760 567.220 1493.920 630.420 ;
        RECT 687.880 554.820 1478.200 567.220 ;
        RECT 105.760 491.620 1493.920 554.820 ;
        RECT 687.880 479.220 1478.200 491.620 ;
        RECT 105.760 416.020 1493.920 479.220 ;
        RECT 687.880 403.620 1478.200 416.020 ;
        RECT 105.760 340.420 1493.920 403.620 ;
        RECT 687.880 328.020 1478.200 340.420 ;
        RECT 105.760 264.820 1493.920 328.020 ;
        RECT 687.880 252.420 1478.200 264.820 ;
        RECT 105.760 189.220 1493.920 252.420 ;
        RECT 687.880 176.820 1478.200 189.220 ;
        RECT 105.760 127.620 1493.920 176.820 ;
  END
END svm_top_ihp
END LIBRARY

